VERSION 5.8 ;
BUSBITCHARS "[]" ;
DIVIDERCHAR "/" ;
UNITS
    DATABASE MICRONS 1000 ;
END UNITS

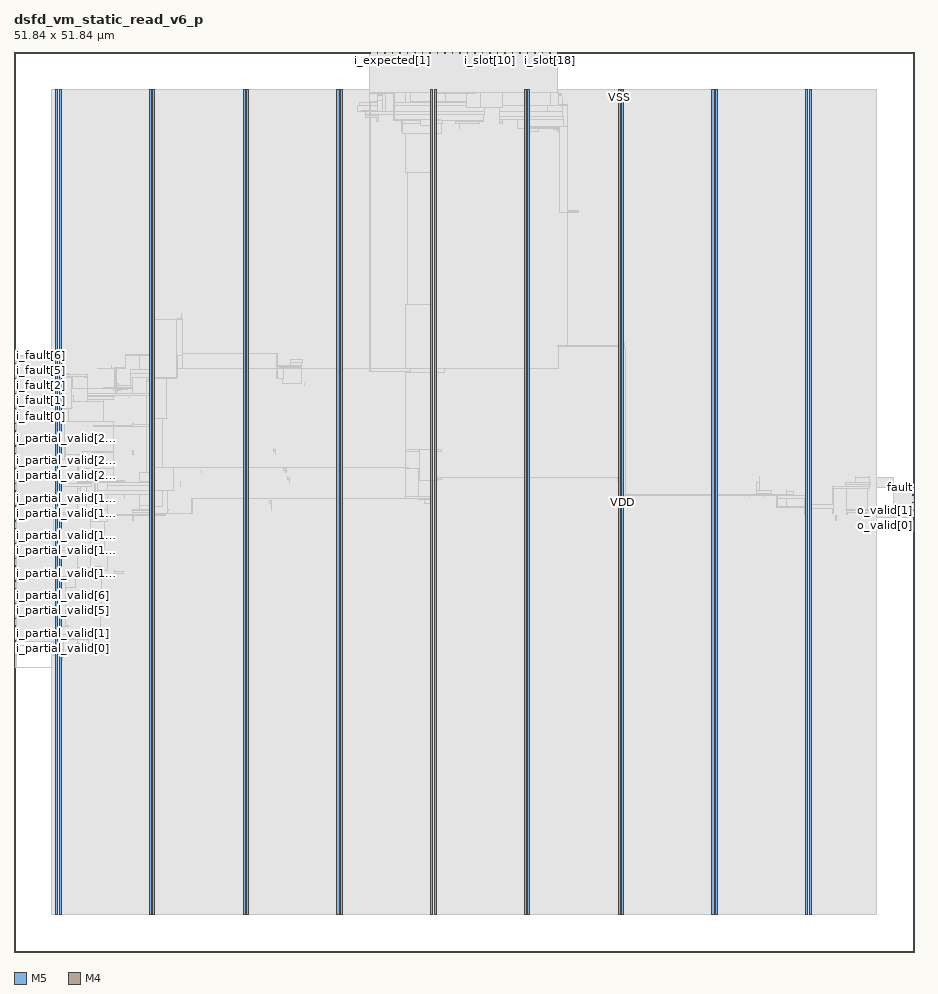
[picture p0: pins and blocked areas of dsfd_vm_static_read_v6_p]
MACRO dsfd_vm_static_read_v6_p
  FOREIGN dsfd_vm_static_read_v6_p 0 0 ;
  CLASS BLOCK ;
  SIZE 51.84 BY 51.84 ;
  PIN ck
    DIRECTION INPUT ;
    USE SIGNAL ;
    PORT
      LAYER M5 ;
        RECT  20.496 51.756 20.52 51.84 ;
    END
  END ck
  PIN fault
    DIRECTION OUTPUT ;
    USE SIGNAL ;
    PORT
      LAYER M4 ;
        RECT  51.756 26.736 51.84 26.76 ;
    END
  END fault
  PIN i_expected[0]
    DIRECTION INPUT ;
    USE SIGNAL ;
    PORT
      LAYER M5 ;
        RECT  21.36 51.756 21.384 51.84 ;
    END
  END i_expected[0]
  PIN i_expected[1]
    DIRECTION INPUT ;
    USE SIGNAL ;
    PORT
      LAYER M5 ;
        RECT  21.792 51.756 21.816 51.84 ;
    END
  END i_expected[1]
  PIN i_expected[2]
    DIRECTION INPUT ;
    USE SIGNAL ;
    PORT
      LAYER M5 ;
        RECT  22.224 51.756 22.248 51.84 ;
    END
  END i_expected[2]
  PIN i_expected[3]
    DIRECTION INPUT ;
    USE SIGNAL ;
    PORT
      LAYER M5 ;
        RECT  22.656 51.756 22.68 51.84 ;
    END
  END i_expected[3]
  PIN i_fault[0]
    DIRECTION INPUT ;
    USE SIGNAL ;
    PORT
      LAYER M4 ;
        RECT  0 31.296 0.084 31.32 ;
    END
  END i_fault[0]
  PIN i_fault[1]
    DIRECTION INPUT ;
    USE SIGNAL ;
    PORT
      LAYER M4 ;
        RECT  0 31.728 0.084 31.752 ;
    END
  END i_fault[1]
  PIN i_fault[2]
    DIRECTION INPUT ;
    USE SIGNAL ;
    PORT
      LAYER M4 ;
        RECT  0 32.16 0.084 32.184 ;
    END
  END i_fault[2]
  PIN i_fault[3]
    DIRECTION INPUT ;
    USE SIGNAL ;
    PORT
      LAYER M4 ;
        RECT  0 32.592 0.084 32.616 ;
    END
  END i_fault[3]
  PIN i_fault[4]
    DIRECTION INPUT ;
    USE SIGNAL ;
    PORT
      LAYER M4 ;
        RECT  0 33.024 0.084 33.048 ;
    END
  END i_fault[4]
  PIN i_fault[5]
    DIRECTION INPUT ;
    USE SIGNAL ;
    PORT
      LAYER M4 ;
        RECT  0 33.456 0.084 33.48 ;
    END
  END i_fault[5]
  PIN i_fault[6]
    DIRECTION INPUT ;
    USE SIGNAL ;
    PORT
      LAYER M4 ;
        RECT  0 33.888 0.084 33.912 ;
    END
  END i_fault[6]
  PIN i_fault[7]
    DIRECTION INPUT ;
    USE SIGNAL ;
    PORT
      LAYER M4 ;
        RECT  0 34.32 0.084 34.344 ;
    END
  END i_fault[7]
  PIN i_partial_valid[0]
    DIRECTION INPUT ;
    USE SIGNAL ;
    PORT
      LAYER M4 ;
        RECT  0 17.472 0.084 17.496 ;
    END
  END i_partial_valid[0]
  PIN i_partial_valid[10]
    DIRECTION INPUT ;
    USE SIGNAL ;
    PORT
      LAYER M4 ;
        RECT  0 21.792 0.084 21.816 ;
    END
  END i_partial_valid[10]
  PIN i_partial_valid[11]
    DIRECTION INPUT ;
    USE SIGNAL ;
    PORT
      LAYER M4 ;
        RECT  0 22.224 0.084 22.248 ;
    END
  END i_partial_valid[11]
  PIN i_partial_valid[12]
    DIRECTION INPUT ;
    USE SIGNAL ;
    PORT
      LAYER M4 ;
        RECT  0 22.656 0.084 22.68 ;
    END
  END i_partial_valid[12]
  PIN i_partial_valid[13]
    DIRECTION INPUT ;
    USE SIGNAL ;
    PORT
      LAYER M4 ;
        RECT  0 23.088 0.084 23.112 ;
    END
  END i_partial_valid[13]
  PIN i_partial_valid[14]
    DIRECTION INPUT ;
    USE SIGNAL ;
    PORT
      LAYER M4 ;
        RECT  0 23.52 0.084 23.544 ;
    END
  END i_partial_valid[14]
  PIN i_partial_valid[15]
    DIRECTION INPUT ;
    USE SIGNAL ;
    PORT
      LAYER M4 ;
        RECT  0 23.952 0.084 23.976 ;
    END
  END i_partial_valid[15]
  PIN i_partial_valid[16]
    DIRECTION INPUT ;
    USE SIGNAL ;
    PORT
      LAYER M4 ;
        RECT  0 24.384 0.084 24.408 ;
    END
  END i_partial_valid[16]
  PIN i_partial_valid[17]
    DIRECTION INPUT ;
    USE SIGNAL ;
    PORT
      LAYER M4 ;
        RECT  0 24.816 0.084 24.84 ;
    END
  END i_partial_valid[17]
  PIN i_partial_valid[18]
    DIRECTION INPUT ;
    USE SIGNAL ;
    PORT
      LAYER M4 ;
        RECT  0 25.248 0.084 25.272 ;
    END
  END i_partial_valid[18]
  PIN i_partial_valid[19]
    DIRECTION INPUT ;
    USE SIGNAL ;
    PORT
      LAYER M4 ;
        RECT  0 25.68 0.084 25.704 ;
    END
  END i_partial_valid[19]
  PIN i_partial_valid[1]
    DIRECTION INPUT ;
    USE SIGNAL ;
    PORT
      LAYER M4 ;
        RECT  0 17.904 0.084 17.928 ;
    END
  END i_partial_valid[1]
  PIN i_partial_valid[20]
    DIRECTION INPUT ;
    USE SIGNAL ;
    PORT
      LAYER M4 ;
        RECT  0 26.112 0.084 26.136 ;
    END
  END i_partial_valid[20]
  PIN i_partial_valid[21]
    DIRECTION INPUT ;
    USE SIGNAL ;
    PORT
      LAYER M4 ;
        RECT  0 26.544 0.084 26.568 ;
    END
  END i_partial_valid[21]
  PIN i_partial_valid[22]
    DIRECTION INPUT ;
    USE SIGNAL ;
    PORT
      LAYER M4 ;
        RECT  0 26.976 0.084 27 ;
    END
  END i_partial_valid[22]
  PIN i_partial_valid[23]
    DIRECTION INPUT ;
    USE SIGNAL ;
    PORT
      LAYER M4 ;
        RECT  0 27.408 0.084 27.432 ;
    END
  END i_partial_valid[23]
  PIN i_partial_valid[24]
    DIRECTION INPUT ;
    USE SIGNAL ;
    PORT
      LAYER M4 ;
        RECT  0 27.84 0.084 27.864 ;
    END
  END i_partial_valid[24]
  PIN i_partial_valid[25]
    DIRECTION INPUT ;
    USE SIGNAL ;
    PORT
      LAYER M4 ;
        RECT  0 28.272 0.084 28.296 ;
    END
  END i_partial_valid[25]
  PIN i_partial_valid[26]
    DIRECTION INPUT ;
    USE SIGNAL ;
    PORT
      LAYER M4 ;
        RECT  0 28.704 0.084 28.728 ;
    END
  END i_partial_valid[26]
  PIN i_partial_valid[27]
    DIRECTION INPUT ;
    USE SIGNAL ;
    PORT
      LAYER M4 ;
        RECT  0 29.136 0.084 29.16 ;
    END
  END i_partial_valid[27]
  PIN i_partial_valid[28]
    DIRECTION INPUT ;
    USE SIGNAL ;
    PORT
      LAYER M4 ;
        RECT  0 29.568 0.084 29.592 ;
    END
  END i_partial_valid[28]
  PIN i_partial_valid[29]
    DIRECTION INPUT ;
    USE SIGNAL ;
    PORT
      LAYER M4 ;
        RECT  0 30 0.084 30.024 ;
    END
  END i_partial_valid[29]
  PIN i_partial_valid[2]
    DIRECTION INPUT ;
    USE SIGNAL ;
    PORT
      LAYER M4 ;
        RECT  0 18.336 0.084 18.36 ;
    END
  END i_partial_valid[2]
  PIN i_partial_valid[30]
    DIRECTION INPUT ;
    USE SIGNAL ;
    PORT
      LAYER M4 ;
        RECT  0 30.432 0.084 30.456 ;
    END
  END i_partial_valid[30]
  PIN i_partial_valid[31]
    DIRECTION INPUT ;
    USE SIGNAL ;
    PORT
      LAYER M4 ;
        RECT  0 30.864 0.084 30.888 ;
    END
  END i_partial_valid[31]
  PIN i_partial_valid[3]
    DIRECTION INPUT ;
    USE SIGNAL ;
    PORT
      LAYER M4 ;
        RECT  0 18.768 0.084 18.792 ;
    END
  END i_partial_valid[3]
  PIN i_partial_valid[4]
    DIRECTION INPUT ;
    USE SIGNAL ;
    PORT
      LAYER M4 ;
        RECT  0 19.2 0.084 19.224 ;
    END
  END i_partial_valid[4]
  PIN i_partial_valid[5]
    DIRECTION INPUT ;
    USE SIGNAL ;
    PORT
      LAYER M4 ;
        RECT  0 19.632 0.084 19.656 ;
    END
  END i_partial_valid[5]
  PIN i_partial_valid[6]
    DIRECTION INPUT ;
    USE SIGNAL ;
    PORT
      LAYER M4 ;
        RECT  0 20.064 0.084 20.088 ;
    END
  END i_partial_valid[6]
  PIN i_partial_valid[7]
    DIRECTION INPUT ;
    USE SIGNAL ;
    PORT
      LAYER M4 ;
        RECT  0 20.496 0.084 20.52 ;
    END
  END i_partial_valid[7]
  PIN i_partial_valid[8]
    DIRECTION INPUT ;
    USE SIGNAL ;
    PORT
      LAYER M4 ;
        RECT  0 20.928 0.084 20.952 ;
    END
  END i_partial_valid[8]
  PIN i_partial_valid[9]
    DIRECTION INPUT ;
    USE SIGNAL ;
    PORT
      LAYER M4 ;
        RECT  0 21.36 0.084 21.384 ;
    END
  END i_partial_valid[9]
  PIN i_slot[0]
    DIRECTION INPUT ;
    USE SIGNAL ;
    PORT
      LAYER M5 ;
        RECT  23.088 51.756 23.112 51.84 ;
    END
  END i_slot[0]
  PIN i_slot[10]
    DIRECTION INPUT ;
    USE SIGNAL ;
    PORT
      LAYER M5 ;
        RECT  27.408 51.756 27.432 51.84 ;
    END
  END i_slot[10]
  PIN i_slot[11]
    DIRECTION INPUT ;
    USE SIGNAL ;
    PORT
      LAYER M5 ;
        RECT  27.84 51.756 27.864 51.84 ;
    END
  END i_slot[11]
  PIN i_slot[12]
    DIRECTION INPUT ;
    USE SIGNAL ;
    PORT
      LAYER M5 ;
        RECT  28.272 51.756 28.296 51.84 ;
    END
  END i_slot[12]
  PIN i_slot[13]
    DIRECTION INPUT ;
    USE SIGNAL ;
    PORT
      LAYER M5 ;
        RECT  28.704 51.756 28.728 51.84 ;
    END
  END i_slot[13]
  PIN i_slot[14]
    DIRECTION INPUT ;
    USE SIGNAL ;
    PORT
      LAYER M5 ;
        RECT  29.136 51.756 29.16 51.84 ;
    END
  END i_slot[14]
  PIN i_slot[15]
    DIRECTION INPUT ;
    USE SIGNAL ;
    PORT
      LAYER M5 ;
        RECT  29.568 51.756 29.592 51.84 ;
    END
  END i_slot[15]
  PIN i_slot[16]
    DIRECTION INPUT ;
    USE SIGNAL ;
    PORT
      LAYER M5 ;
        RECT  30 51.756 30.024 51.84 ;
    END
  END i_slot[16]
  PIN i_slot[17]
    DIRECTION INPUT ;
    USE SIGNAL ;
    PORT
      LAYER M5 ;
        RECT  30.432 51.756 30.456 51.84 ;
    END
  END i_slot[17]
  PIN i_slot[18]
    DIRECTION INPUT ;
    USE SIGNAL ;
    PORT
      LAYER M5 ;
        RECT  30.864 51.756 30.888 51.84 ;
    END
  END i_slot[18]
  PIN i_slot[19]
    DIRECTION INPUT ;
    USE SIGNAL ;
    PORT
      LAYER M5 ;
        RECT  31.296 51.756 31.32 51.84 ;
    END
  END i_slot[19]
  PIN i_slot[1]
    DIRECTION INPUT ;
    USE SIGNAL ;
    PORT
      LAYER M5 ;
        RECT  23.52 51.756 23.544 51.84 ;
    END
  END i_slot[1]
  PIN i_slot[2]
    DIRECTION INPUT ;
    USE SIGNAL ;
    PORT
      LAYER M5 ;
        RECT  23.952 51.756 23.976 51.84 ;
    END
  END i_slot[2]
  PIN i_slot[3]
    DIRECTION INPUT ;
    USE SIGNAL ;
    PORT
      LAYER M5 ;
        RECT  24.384 51.756 24.408 51.84 ;
    END
  END i_slot[3]
  PIN i_slot[4]
    DIRECTION INPUT ;
    USE SIGNAL ;
    PORT
      LAYER M5 ;
        RECT  24.816 51.756 24.84 51.84 ;
    END
  END i_slot[4]
  PIN i_slot[5]
    DIRECTION INPUT ;
    USE SIGNAL ;
    PORT
      LAYER M5 ;
        RECT  25.248 51.756 25.272 51.84 ;
    END
  END i_slot[5]
  PIN i_slot[6]
    DIRECTION INPUT ;
    USE SIGNAL ;
    PORT
      LAYER M5 ;
        RECT  25.68 51.756 25.704 51.84 ;
    END
  END i_slot[6]
  PIN i_slot[7]
    DIRECTION INPUT ;
    USE SIGNAL ;
    PORT
      LAYER M5 ;
        RECT  26.112 51.756 26.136 51.84 ;
    END
  END i_slot[7]
  PIN i_slot[8]
    DIRECTION INPUT ;
    USE SIGNAL ;
    PORT
      LAYER M5 ;
        RECT  26.544 51.756 26.568 51.84 ;
    END
  END i_slot[8]
  PIN i_slot[9]
    DIRECTION INPUT ;
    USE SIGNAL ;
    PORT
      LAYER M5 ;
        RECT  26.976 51.756 27 51.84 ;
    END
  END i_slot[9]
  PIN o_valid[0]
    DIRECTION OUTPUT ;
    USE SIGNAL ;
    PORT
      LAYER M4 ;
        RECT  51.756 25.008 51.84 25.032 ;
    END
  END o_valid[0]
  PIN o_valid[1]
    DIRECTION OUTPUT ;
    USE SIGNAL ;
    PORT
      LAYER M4 ;
        RECT  51.756 25.44 51.84 25.464 ;
    END
  END o_valid[1]
  PIN o_valid[2]
    DIRECTION OUTPUT ;
    USE SIGNAL ;
    PORT
      LAYER M4 ;
        RECT  51.756 25.872 51.84 25.896 ;
    END
  END o_valid[2]
  PIN o_valid[3]
    DIRECTION OUTPUT ;
    USE SIGNAL ;
    PORT
      LAYER M4 ;
        RECT  51.756 26.304 51.84 26.328 ;
    END
  END o_valid[3]
  PIN rst_n
    DIRECTION INPUT ;
    USE SIGNAL ;
    PORT
      LAYER M5 ;
        RECT  20.928 51.756 20.952 51.84 ;
    END
  END rst_n
  PIN VDD
    DIRECTION INOUT ;
    USE POWER ;
    PORT
      LAYER M5 ;
        RECT  45.792 2.151 45.912 49.689 ;
        RECT  40.392 2.151 40.512 49.689 ;
        RECT  34.992 2.151 35.112 49.689 ;
        RECT  29.592 2.151 29.712 49.689 ;
        RECT  24.192 2.151 24.312 49.689 ;
        RECT  18.792 2.151 18.912 49.689 ;
        RECT  13.392 2.151 13.512 49.689 ;
        RECT  7.992 2.151 8.112 49.689 ;
        RECT  2.592 2.151 2.712 49.689 ;
    END
  END VDD
  PIN VSS
    DIRECTION INOUT ;
    USE GROUND ;
    PORT
      LAYER M5 ;
        RECT  45.6 2.137 45.72 49.703 ;
        RECT  40.2 2.137 40.32 49.703 ;
        RECT  34.8 2.137 34.92 49.703 ;
        RECT  29.4 2.137 29.52 49.703 ;
        RECT  24 2.137 24.12 49.703 ;
        RECT  18.6 2.137 18.72 49.703 ;
        RECT  13.2 2.137 13.32 49.703 ;
        RECT  7.8 2.137 7.92 49.703 ;
        RECT  2.4 2.137 2.52 49.703 ;
    END
  END VSS
  # OT_OBS_CLOSED layer=M5 d_um=1.536 added=2
  OBS
    LAYER RVTN ;
     RECT  2.16 2.16 49.68 2.295 ;
     RECT  2.16 2.565 49.68 2.835 ;
     RECT  2.16 3.105 49.68 3.375 ;
     RECT  2.16 3.645 49.68 3.915 ;
     RECT  2.16 4.185 49.68 4.455 ;
     RECT  2.16 4.725 49.68 4.995 ;
     RECT  2.16 5.265 49.68 5.535 ;
     RECT  2.16 5.805 49.68 6.075 ;
     RECT  2.16 6.345 49.68 6.615 ;
     RECT  2.16 6.885 49.68 7.155 ;
     RECT  2.16 7.425 49.68 7.695 ;
     RECT  2.16 7.965 49.68 8.235 ;
     RECT  2.16 8.505 49.68 8.775 ;
     RECT  2.16 9.045 49.68 9.315 ;
     RECT  2.16 9.585 49.68 9.855 ;
     RECT  2.16 10.125 49.68 10.395 ;
     RECT  2.16 10.665 49.68 10.935 ;
     RECT  2.16 11.205 49.68 11.475 ;
     RECT  2.16 11.745 49.68 12.015 ;
     RECT  2.16 12.285 49.68 12.555 ;
     RECT  2.16 12.825 49.68 13.095 ;
     RECT  2.16 13.365 49.68 13.635 ;
     RECT  2.16 13.905 49.68 14.175 ;
     RECT  2.16 14.445 49.68 14.715 ;
     RECT  2.16 14.985 49.68 15.255 ;
     RECT  2.16 15.525 49.68 15.795 ;
     RECT  2.16 16.065 49.68 16.335 ;
     RECT  2.16 16.605 49.68 16.875 ;
     RECT  2.16 17.145 49.68 17.415 ;
     RECT  2.16 17.685 49.68 17.955 ;
     RECT  2.16 18.225 49.68 18.495 ;
     RECT  2.16 18.765 49.68 19.035 ;
     RECT  2.16 19.305 49.68 19.575 ;
     RECT  2.16 19.845 49.68 20.115 ;
     RECT  2.16 20.385 49.68 20.655 ;
     RECT  2.16 20.925 49.68 21.195 ;
     RECT  2.16 21.465 49.68 21.735 ;
     RECT  2.16 22.005 49.68 22.275 ;
     RECT  2.16 22.545 49.68 22.815 ;
     RECT  2.16 23.085 49.68 23.355 ;
     RECT  2.16 23.625 49.68 23.895 ;
     RECT  2.16 24.165 49.68 24.435 ;
     RECT  2.16 24.705 49.68 24.975 ;
     RECT  2.16 25.245 49.68 25.515 ;
     RECT  2.16 25.785 49.68 26.055 ;
     RECT  2.16 26.325 49.68 26.595 ;
     RECT  2.16 26.865 49.68 27.135 ;
     RECT  2.16 27.405 49.68 27.675 ;
     RECT  2.16 27.945 49.68 28.215 ;
     RECT  2.16 28.485 49.68 28.755 ;
     RECT  2.16 29.025 49.68 29.295 ;
     RECT  2.16 29.565 49.68 29.835 ;
     RECT  2.16 30.105 49.68 30.375 ;
     RECT  2.16 30.645 49.68 30.915 ;
     RECT  2.16 31.185 49.68 31.455 ;
     RECT  2.16 31.725 49.68 31.995 ;
     RECT  2.16 32.265 49.68 32.535 ;
     RECT  2.16 32.805 49.68 33.075 ;
     RECT  2.16 33.345 49.68 33.615 ;
     RECT  2.16 33.885 49.68 34.155 ;
     RECT  2.16 34.425 49.68 34.695 ;
     RECT  2.16 34.965 49.68 35.235 ;
     RECT  2.16 35.505 49.68 35.775 ;
     RECT  2.16 36.045 49.68 36.315 ;
     RECT  2.16 36.585 49.68 36.855 ;
     RECT  2.16 37.125 49.68 37.395 ;
     RECT  2.16 37.665 49.68 37.935 ;
     RECT  2.16 38.205 49.68 38.475 ;
     RECT  2.16 38.745 49.68 39.015 ;
     RECT  2.16 39.285 49.68 39.555 ;
     RECT  2.16 39.825 49.68 40.095 ;
     RECT  2.16 40.365 49.68 40.635 ;
     RECT  2.16 40.905 49.68 41.175 ;
     RECT  2.16 41.445 49.68 41.715 ;
     RECT  2.16 41.985 49.68 42.255 ;
     RECT  2.16 42.525 49.68 42.795 ;
     RECT  2.16 43.065 49.68 43.335 ;
     RECT  2.16 43.605 49.68 43.875 ;
     RECT  2.16 44.145 49.68 44.415 ;
     RECT  2.16 44.685 49.68 44.955 ;
     RECT  2.16 45.225 49.68 45.495 ;
     RECT  2.16 45.765 49.68 46.035 ;
     RECT  2.16 46.305 49.68 46.575 ;
     RECT  2.16 46.845 49.68 47.115 ;
     RECT  2.16 47.385 49.68 47.655 ;
     RECT  2.16 47.925 49.68 48.195 ;
     RECT  2.16 48.465 49.68 48.735 ;
     RECT  2.16 49.005 49.68 49.275 ;
     RECT  2.16 49.545 49.68 49.68 ;
    LAYER RVTP ;
     RECT  2.16 2.295 49.68 2.565 ;
     RECT  2.16 2.835 49.68 3.105 ;
     RECT  2.16 3.375 49.68 3.645 ;
     RECT  2.16 3.915 49.68 4.185 ;
     RECT  2.16 4.455 49.68 4.725 ;
     RECT  2.16 4.995 49.68 5.265 ;
     RECT  2.16 5.535 49.68 5.805 ;
     RECT  2.16 6.075 49.68 6.345 ;
     RECT  2.16 6.615 49.68 6.885 ;
     RECT  2.16 7.155 49.68 7.425 ;
     RECT  2.16 7.695 49.68 7.965 ;
     RECT  2.16 8.235 49.68 8.505 ;
     RECT  2.16 8.775 49.68 9.045 ;
     RECT  2.16 9.315 49.68 9.585 ;
     RECT  2.16 9.855 49.68 10.125 ;
     RECT  2.16 10.395 49.68 10.665 ;
     RECT  2.16 10.935 49.68 11.205 ;
     RECT  2.16 11.475 49.68 11.745 ;
     RECT  2.16 12.015 49.68 12.285 ;
     RECT  2.16 12.555 49.68 12.825 ;
     RECT  2.16 13.095 49.68 13.365 ;
     RECT  2.16 13.635 49.68 13.905 ;
     RECT  2.16 14.175 49.68 14.445 ;
     RECT  2.16 14.715 49.68 14.985 ;
     RECT  2.16 15.255 49.68 15.525 ;
     RECT  2.16 15.795 49.68 16.065 ;
     RECT  2.16 16.335 49.68 16.605 ;
     RECT  2.16 16.875 49.68 17.145 ;
     RECT  2.16 17.415 49.68 17.685 ;
     RECT  2.16 17.955 49.68 18.225 ;
     RECT  2.16 18.495 49.68 18.765 ;
     RECT  2.16 19.035 49.68 19.305 ;
     RECT  2.16 19.575 49.68 19.845 ;
     RECT  2.16 20.115 49.68 20.385 ;
     RECT  2.16 20.655 49.68 20.925 ;
     RECT  2.16 21.195 49.68 21.465 ;
     RECT  2.16 21.735 49.68 22.005 ;
     RECT  2.16 22.275 49.68 22.545 ;
     RECT  2.16 22.815 49.68 23.085 ;
     RECT  2.16 23.355 49.68 23.625 ;
     RECT  2.16 23.895 49.68 24.165 ;
     RECT  2.16 24.435 49.68 24.705 ;
     RECT  2.16 24.975 49.68 25.245 ;
     RECT  2.16 25.515 49.68 25.785 ;
     RECT  2.16 26.055 49.68 26.325 ;
     RECT  2.16 26.595 49.68 26.865 ;
     RECT  2.16 27.135 49.68 27.405 ;
     RECT  2.16 27.675 49.68 27.945 ;
     RECT  2.16 28.215 49.68 28.485 ;
     RECT  2.16 28.755 49.68 29.025 ;
     RECT  2.16 29.295 49.68 29.565 ;
     RECT  2.16 29.835 49.68 30.105 ;
     RECT  2.16 30.375 49.68 30.645 ;
     RECT  2.16 30.915 49.68 31.185 ;
     RECT  2.16 31.455 49.68 31.725 ;
     RECT  2.16 31.995 49.68 32.265 ;
     RECT  2.16 32.535 49.68 32.805 ;
     RECT  2.16 33.075 49.68 33.345 ;
     RECT  2.16 33.615 49.68 33.885 ;
     RECT  2.16 34.155 49.68 34.425 ;
     RECT  2.16 34.695 49.68 34.965 ;
     RECT  2.16 35.235 49.68 35.505 ;
     RECT  2.16 35.775 49.68 36.045 ;
     RECT  2.16 36.315 49.68 36.585 ;
     RECT  2.16 36.855 49.68 37.125 ;
     RECT  2.16 37.395 49.68 37.665 ;
     RECT  2.16 37.935 49.68 38.205 ;
     RECT  2.16 38.475 49.68 38.745 ;
     RECT  2.16 39.015 49.68 39.285 ;
     RECT  2.16 39.555 49.68 39.825 ;
     RECT  2.16 40.095 49.68 40.365 ;
     RECT  2.16 40.635 49.68 40.905 ;
     RECT  2.16 41.175 49.68 41.445 ;
     RECT  2.16 41.715 49.68 41.985 ;
     RECT  2.16 42.255 49.68 42.525 ;
     RECT  2.16 42.795 49.68 43.065 ;
     RECT  2.16 43.335 49.68 43.605 ;
     RECT  2.16 43.875 49.68 44.145 ;
     RECT  2.16 44.415 49.68 44.685 ;
     RECT  2.16 44.955 49.68 45.225 ;
     RECT  2.16 45.495 49.68 45.765 ;
     RECT  2.16 46.035 49.68 46.305 ;
     RECT  2.16 46.575 49.68 46.845 ;
     RECT  2.16 47.115 49.68 47.385 ;
     RECT  2.16 47.655 49.68 47.925 ;
     RECT  2.16 48.195 49.68 48.465 ;
     RECT  2.16 48.735 49.68 49.005 ;
     RECT  2.16 49.275 49.68 49.545 ;
    LAYER M1 ;
     RECT  2.16 2.151 49.68 49.689 ;
    LAYER M2 ;
     RECT  0.103 16.38 2.16 16.398 ;
     RECT  0.103 17.658 2.16 17.676 ;
     RECT  0.103 22.05 2.16 22.068 ;
     RECT  0.103 26.91 2.16 26.928 ;
     RECT  0.103 28.962 2.16 28.98 ;
     RECT  2.16 2.151 49.68 49.689 ;
     RECT  49.68 26.766 50.675 27.324 ;
     RECT  49.68 25.02 50.711 25.47 ;
     RECT  50.675 26.766 50.711 26.784 ;
     RECT  50.711 25.326 50.747 25.344 ;
    LAYER M3 ;
     RECT  2.415 2.143 2.505 2.413 ;
     RECT  7.815 2.143 7.905 2.413 ;
     RECT  13.215 2.143 13.305 2.413 ;
     RECT  18.615 2.143 18.705 2.413 ;
     RECT  24.015 2.143 24.105 2.413 ;
     RECT  29.415 2.143 29.505 2.413 ;
     RECT  34.815 2.143 34.905 2.413 ;
     RECT  40.215 2.143 40.305 2.413 ;
     RECT  45.615 2.143 45.705 2.413 ;
     RECT  2.415 2.413 2.697 16.411 ;
     RECT  2.412 16.411 2.697 16.501 ;
     RECT  2.412 16.501 2.754 16.807 ;
     RECT  2.412 16.807 2.79 16.951 ;
     RECT  2.412 16.951 2.826 17.077 ;
     RECT  2.304 17.077 2.826 17.419 ;
     RECT  3.672 17.581 3.69 17.725 ;
     RECT  3.672 17.725 4.302 17.761 ;
     RECT  2.304 17.419 2.862 17.995 ;
     RECT  3.636 17.761 4.302 17.995 ;
     RECT  2.304 17.995 4.302 18.031 ;
     RECT  2.304 18.031 4.77 18.301 ;
     RECT  0.108 16.375 0.126 18.797 ;
     RECT  2.304 18.301 4.986 19.651 ;
     RECT  5.796 21.667 5.814 21.811 ;
     RECT  5.796 21.811 6.282 21.929 ;
     RECT  5.796 21.929 5.814 21.965 ;
     RECT  2.304 19.651 5.058 21.973 ;
     RECT  0.108 21.355 0.126 22.253 ;
     RECT  2.304 21.973 5.382 22.891 ;
     RECT  2.304 22.891 5.706 23.009 ;
     RECT  2.304 23.009 5.382 23.081 ;
     RECT  2.304 23.081 5.202 23.431 ;
     RECT  2.268 23.431 5.202 24.781 ;
     RECT  7.815 2.413 8.097 25.141 ;
     RECT  47.34 24.871 47.358 25.169 ;
     RECT  6.84 24.871 6.858 25.177 ;
     RECT  7.815 25.141 8.73 25.177 ;
     RECT  45.615 2.413 45.897 25.213 ;
     RECT  48.96 25.015 48.978 25.285 ;
     RECT  6.84 25.177 8.73 25.321 ;
     RECT  47.952 25.177 48.006 25.321 ;
     RECT  48.96 25.285 49.158 25.321 ;
     RECT  50.688 25.003 50.706 25.321 ;
     RECT  6.84 25.321 8.802 25.411 ;
     RECT  47.952 25.321 49.158 25.411 ;
     RECT  2.268 24.781 5.382 25.475 ;
     RECT  50.688 25.321 50.742 25.475 ;
     RECT  6.84 25.411 8.874 25.511 ;
     RECT  47.952 25.411 49.338 25.511 ;
     RECT  45.504 25.213 45.897 25.519 ;
     RECT  47.16 25.249 47.178 25.519 ;
     RECT  43.92 25.627 43.938 25.681 ;
     RECT  7.2 25.511 8.802 25.709 ;
     RECT  45.504 25.519 47.178 25.781 ;
     RECT  14.832 25.411 14.85 25.825 ;
     RECT  24.015 2.413 24.297 25.825 ;
     RECT  50.724 25.475 50.742 25.901 ;
     RECT  14.724 25.825 14.85 25.979 ;
     RECT  14.724 25.979 14.742 26.015 ;
     RECT  23.652 25.825 24.297 26.059 ;
     RECT  23.292 26.059 24.297 26.095 ;
     RECT  43.92 25.681 44.514 26.095 ;
     RECT  45.504 25.781 45.897 26.095 ;
     RECT  22.392 26.095 22.41 26.131 ;
     RECT  23.184 26.095 24.297 26.131 ;
     RECT  22.392 26.131 24.297 26.141 ;
     RECT  22.536 26.141 24.297 26.249 ;
     RECT  43.92 26.095 45.897 26.285 ;
     RECT  42.372 26.257 42.39 26.293 ;
     RECT  43.164 26.257 43.182 26.293 ;
     RECT  6.336 26.095 6.354 26.329 ;
     RECT  7.2 25.709 8.334 26.329 ;
     RECT  42.372 26.293 43.182 26.333 ;
     RECT  43.92 26.285 44.874 26.333 ;
     RECT  2.304 25.475 5.382 26.365 ;
     RECT  6.336 26.329 8.334 26.365 ;
     RECT  42.768 26.333 43.182 26.401 ;
     RECT  44.496 26.333 44.874 26.519 ;
     RECT  42.768 26.401 43.65 26.555 ;
     RECT  2.304 26.365 8.334 26.599 ;
     RECT  44.496 26.519 44.514 26.627 ;
     RECT  47.16 25.781 47.178 26.671 ;
     RECT  47.952 25.511 49.158 26.671 ;
     RECT  2.304 26.599 8.514 26.699 ;
     RECT  50.652 26.299 50.67 26.731 ;
     RECT  2.304 26.699 8.442 26.789 ;
     RECT  47.16 26.671 49.266 26.789 ;
     RECT  50.652 26.731 50.706 26.789 ;
     RECT  47.88 26.789 49.266 26.905 ;
     RECT  2.304 26.789 8.118 27.059 ;
     RECT  42.768 26.555 42.93 27.059 ;
     RECT  47.88 26.905 49.338 27.059 ;
     RECT  2.304 27.059 6.354 27.095 ;
     RECT  7.2 27.059 8.118 27.095 ;
     RECT  9.576 26.797 9.594 27.095 ;
     RECT  2.376 27.095 6.354 27.131 ;
     RECT  23.292 26.249 24.297 27.163 ;
     RECT  34.815 2.413 35.097 27.163 ;
     RECT  15.876 27.031 15.894 27.211 ;
     RECT  23.292 27.163 24.39 27.211 ;
     RECT  15.732 27.211 15.894 27.329 ;
     RECT  23.292 27.211 24.606 27.329 ;
     RECT  48.456 27.059 49.266 27.329 ;
     RECT  50.652 26.789 50.67 27.329 ;
     RECT  23.292 27.329 24.39 27.341 ;
     RECT  34.776 27.163 35.097 27.341 ;
     RECT  15.732 27.329 15.75 27.365 ;
     RECT  48.456 27.329 48.474 27.365 ;
     RECT  49.248 27.329 49.266 27.365 ;
     RECT  42.912 27.059 42.93 27.401 ;
     RECT  0.108 26.905 0.126 27.437 ;
     RECT  7.2 27.095 8.097 27.599 ;
     RECT  10.8 27.607 10.818 27.707 ;
     RECT  15.66 27.607 15.678 27.751 ;
     RECT  2.376 27.131 5.706 27.835 ;
     RECT  15.516 27.751 15.678 27.869 ;
     RECT  22.536 26.249 22.554 27.877 ;
     RECT  23.292 27.341 24.297 27.877 ;
     RECT  15.516 27.869 15.534 27.905 ;
     RECT  15.048 28.651 15.066 28.831 ;
     RECT  22.536 27.877 24.297 28.831 ;
     RECT  6.84 28.651 6.858 28.859 ;
     RECT  14.94 28.831 15.066 28.949 ;
     RECT  22.536 28.831 24.606 28.949 ;
     RECT  14.94 28.949 14.958 28.985 ;
     RECT  0.108 28.957 0.126 29.165 ;
     RECT  6.84 30.283 6.858 30.413 ;
     RECT  2.304 27.835 5.706 30.569 ;
     RECT  2.304 30.569 5.166 31.721 ;
     RECT  4.212 31.721 5.166 31.801 ;
     RECT  4.212 31.801 5.706 31.999 ;
     RECT  4.212 31.999 5.778 32.035 ;
     RECT  6.66 31.927 6.678 32.035 ;
     RECT  7.632 27.599 8.097 32.035 ;
     RECT  2.304 31.721 3.402 32.063 ;
     RECT  4.212 32.035 6.678 32.071 ;
     RECT  7.632 32.035 8.442 32.071 ;
     RECT  2.304 32.063 2.97 32.099 ;
     RECT  2.304 32.099 2.934 32.189 ;
     RECT  4.212 32.071 8.442 32.189 ;
     RECT  2.304 32.189 2.862 32.225 ;
     RECT  4.212 32.189 6.822 32.477 ;
     RECT  5.148 32.477 6.822 32.495 ;
     RECT  5.76 32.495 6.822 32.639 ;
     RECT  5.76 32.639 5.994 32.729 ;
     RECT  16.74 32.611 16.758 32.729 ;
     RECT  15.48 32.737 15.498 32.773 ;
     RECT  16.272 32.737 16.578 32.773 ;
     RECT  7.632 32.189 8.442 32.881 ;
     RECT  7.632 32.881 8.766 32.999 ;
     RECT  2.304 32.225 2.697 33.067 ;
     RECT  4.212 32.477 4.23 33.115 ;
     RECT  6.732 32.639 6.822 33.115 ;
     RECT  7.632 32.999 8.55 33.115 ;
     RECT  2.304 33.067 3.294 33.151 ;
     RECT  4.068 33.115 4.23 33.151 ;
     RECT  2.304 33.151 4.23 33.269 ;
     RECT  2.304 33.269 3.15 33.305 ;
     RECT  6.732 33.115 8.55 33.341 ;
     RECT  22.536 28.949 24.297 33.355 ;
     RECT  6.732 33.341 8.442 33.539 ;
     RECT  22.536 33.355 24.786 33.539 ;
     RECT  2.304 33.305 2.79 33.575 ;
     RECT  5.76 32.729 5.814 33.595 ;
     RECT  4.824 33.583 4.842 33.629 ;
     RECT  25.884 33.583 25.902 33.629 ;
     RECT  5.76 33.595 6.426 33.647 ;
     RECT  15.48 32.773 16.578 33.691 ;
     RECT  15.264 33.691 16.578 33.739 ;
     RECT  5.616 33.655 5.634 33.809 ;
     RECT  15.12 33.739 16.578 33.809 ;
     RECT  2.415 33.575 2.79 33.917 ;
     RECT  15.912 33.809 16.578 33.961 ;
     RECT  15.912 33.961 16.614 34.115 ;
     RECT  16.596 34.115 16.614 34.151 ;
     RECT  2.415 33.917 2.697 34.315 ;
     RECT  7.2 33.539 8.442 34.349 ;
     RECT  7.2 34.349 8.097 34.357 ;
     RECT  2.34 34.315 2.697 34.385 ;
     RECT  6.408 33.647 6.426 34.397 ;
     RECT  7.164 34.357 8.097 34.397 ;
     RECT  34.815 27.341 35.097 34.795 ;
     RECT  34.815 34.795 35.19 35.069 ;
     RECT  9.396 36.379 9.414 36.475 ;
     RECT  9.396 36.475 9.666 36.509 ;
     RECT  9.648 36.509 9.666 36.779 ;
     RECT  22.536 33.539 24.297 37.319 ;
     RECT  32.508 42.601 32.526 42.715 ;
     RECT  31.86 42.715 32.526 42.719 ;
     RECT  31.86 42.719 31.878 42.755 ;
     RECT  22.644 37.319 24.297 44.887 ;
     RECT  22.572 44.887 24.297 47.119 ;
     RECT  22.572 47.119 24.606 47.155 ;
     RECT  29.415 2.413 29.697 47.281 ;
     RECT  31.392 47.191 31.41 47.281 ;
     RECT  31.32 47.281 31.41 47.353 ;
     RECT  29.415 47.281 30.186 47.461 ;
     RECT  31.068 47.353 31.662 47.461 ;
     RECT  25.668 47.425 25.686 47.695 ;
     RECT  22.356 47.155 24.606 47.731 ;
     RECT  25.668 47.695 26.118 47.731 ;
     RECT  25.452 47.731 26.838 47.821 ;
     RECT  27.972 47.731 28.134 47.821 ;
     RECT  20.952 47.821 20.97 47.857 ;
     RECT  25.452 47.821 26.91 47.857 ;
     RECT  22.356 47.731 24.678 47.893 ;
     RECT  25.452 47.857 27.018 47.893 ;
     RECT  22.356 47.893 27.018 47.899 ;
     RECT  27.936 47.821 28.134 47.965 ;
     RECT  28.98 47.461 31.662 47.965 ;
     RECT  20.88 47.857 20.97 48.091 ;
     RECT  27.936 47.965 31.662 48.119 ;
     RECT  20.232 48.091 20.97 48.199 ;
     RECT  20.232 48.199 21.006 48.235 ;
     RECT  21.888 47.899 27.018 48.235 ;
     RECT  27.936 48.119 31.59 48.389 ;
     RECT  20.232 48.235 27.09 48.424 ;
     RECT  20.052 48.424 27.09 48.433 ;
     RECT  19.764 48.433 27.09 48.731 ;
     RECT  19.872 48.731 27.09 48.763 ;
     RECT  27.936 48.389 30.726 48.763 ;
     RECT  19.872 48.763 30.726 48.929 ;
     RECT  31.572 48.389 31.59 49.199 ;
     RECT  20.7 48.929 30.726 49.315 ;
     RECT  20.7 49.315 31.554 49.379 ;
     RECT  2.415 34.385 2.697 49.427 ;
     RECT  7.815 34.397 8.097 49.427 ;
     RECT  13.215 2.413 13.497 49.427 ;
     RECT  18.615 2.413 18.897 49.427 ;
     RECT  34.815 35.069 35.097 49.427 ;
     RECT  40.215 2.413 40.497 49.427 ;
     RECT  45.615 26.285 45.897 49.427 ;
     RECT  20.772 49.379 31.554 49.469 ;
     RECT  20.952 49.469 31.338 49.517 ;
     RECT  26.856 49.517 30.834 49.565 ;
     RECT  20.952 49.517 21.258 49.577 ;
     RECT  22.104 49.517 25.038 49.577 ;
     RECT  26.856 49.565 30.438 49.577 ;
     RECT  2.415 49.427 2.505 49.697 ;
     RECT  7.815 49.427 7.905 49.697 ;
     RECT  13.215 49.427 13.305 49.697 ;
     RECT  18.615 49.427 18.705 49.697 ;
     RECT  23.832 49.577 24.105 49.697 ;
     RECT  29.415 49.577 29.574 49.697 ;
     RECT  34.815 49.427 34.905 49.697 ;
     RECT  40.215 49.427 40.305 49.697 ;
     RECT  45.615 49.427 45.705 49.697 ;
     RECT  29.556 49.697 29.574 49.805 ;
     RECT  22.104 49.577 22.122 50.765 ;
     RECT  23.832 49.697 23.85 50.765 ;
     RECT  25.02 49.577 25.038 50.765 ;
     RECT  27.288 49.577 27.306 50.765 ;
    LAYER M4 ;
     RECT  0.06 17.472 0.137 34.344 ;
     RECT  0.137 17.904 2.408 34.344 ;
     RECT  2.408 2.148 2.512 49.692 ;
     RECT  2.512 2.418 2.704 49.422 ;
     RECT  2.704 32.448 2.801 33.912 ;
     RECT  2.704 19.872 2.909 26.712 ;
     RECT  2.909 19.872 2.915 23.928 ;
     RECT  2.909 24.912 2.945 26.712 ;
     RECT  2.704 27.696 2.981 29.112 ;
     RECT  2.704 18.768 3.125 18.792 ;
     RECT  2.704 30.576 3.125 31.368 ;
     RECT  3.125 31.344 3.347 31.368 ;
     RECT  2.801 32.448 3.347 33.096 ;
     RECT  2.945 24.912 3.449 25.032 ;
     RECT  2.915 20.976 3.557 23.928 ;
     RECT  3.557 21.648 3.683 23.928 ;
     RECT  2.981 27.696 3.737 28.632 ;
     RECT  2.915 19.872 3.773 19.896 ;
     RECT  2.945 26.112 3.805 26.712 ;
     RECT  3.737 28.08 3.809 28.632 ;
     RECT  3.449 25.008 3.881 25.032 ;
     RECT  3.809 28.224 3.949 28.632 ;
     RECT  3.805 26.112 4.165 27.048 ;
     RECT  3.683 22.176 4.403 23.928 ;
     RECT  3.949 28.224 4.493 28.824 ;
     RECT  4.403 23.328 4.637 23.352 ;
     RECT  4.165 25.152 4.637 27.048 ;
     RECT  4.637 26.352 4.709 27.048 ;
     RECT  4.709 26.496 4.817 27.048 ;
     RECT  4.403 22.176 5.033 22.2 ;
     RECT  4.817 26.592 5.393 27.048 ;
     RECT  3.347 32.448 5.713 32.472 ;
     RECT  4.493 28.8 5.717 28.824 ;
     RECT  5.713 32.352 5.845 32.472 ;
     RECT  5.845 32.208 5.932 32.472 ;
     RECT  5.932 32.352 5.933 32.472 ;
     RECT  5.933 32.352 6.113 32.424 ;
     RECT  4.813 33.6 6.397 33.624 ;
     RECT  6.397 33.6 6.437 34.392 ;
     RECT  6.113 32.4 6.545 32.424 ;
     RECT  4.561 30.288 6.829 30.312 ;
     RECT  4.637 25.152 7.808 25.176 ;
     RECT  5.393 26.592 7.808 26.856 ;
     RECT  6.829 30.288 7.808 30.408 ;
     RECT  6.437 34.368 7.808 34.392 ;
     RECT  7.808 2.148 7.912 49.692 ;
     RECT  7.912 2.418 8.104 49.422 ;
     RECT  8.104 30.384 8.579 30.744 ;
     RECT  8.104 25.248 8.813 26.616 ;
     RECT  8.579 30.72 8.819 30.744 ;
     RECT  8.813 26.592 9.203 26.616 ;
     RECT  8.104 33.072 9.349 33.096 ;
     RECT  8.104 34.368 9.349 34.392 ;
     RECT  9.349 33.072 9.395 34.392 ;
     RECT  9.341 36.384 9.425 36.408 ;
     RECT  9.395 33.6 9.685 34.392 ;
     RECT  9.637 36.48 9.731 36.504 ;
     RECT  8.813 25.248 10.213 25.272 ;
     RECT  10.213 25.248 10.259 26.136 ;
     RECT  10.259 26.112 13.208 26.136 ;
     RECT  9.157 27.888 13.208 27.912 ;
     RECT  9.685 33.6 13.208 34.488 ;
     RECT  13.208 2.148 13.312 49.692 ;
     RECT  13.312 2.418 13.504 49.422 ;
     RECT  13.504 33.6 15.109 34.488 ;
     RECT  15.109 33.024 15.155 34.488 ;
     RECT  15.155 33.024 15.509 33.624 ;
     RECT  13.504 26.112 18.608 26.136 ;
     RECT  13.504 27.888 18.608 27.912 ;
     RECT  15.509 33.6 18.608 33.624 ;
     RECT  18.608 2.148 18.712 49.692 ;
     RECT  18.712 2.418 18.904 49.422 ;
     RECT  18.904 33.6 20.485 33.624 ;
     RECT  20.041 48.432 20.917 48.456 ;
     RECT  20.917 48.432 21.229 49.032 ;
     RECT  21.229 48.432 21.395 49.56 ;
     RECT  21.395 48.432 21.877 49.512 ;
     RECT  21.877 47.904 21.917 49.512 ;
     RECT  22.093 50.736 22.259 50.76 ;
     RECT  21.917 47.904 22.316 47.928 ;
     RECT  22.316 47.28 22.403 47.928 ;
     RECT  18.904 26.112 22.421 26.136 ;
     RECT  21.917 48.912 22.525 49.512 ;
     RECT  18.904 27.888 22.745 27.912 ;
     RECT  20.485 33.456 22.813 33.624 ;
     RECT  22.525 48.912 22.853 49.56 ;
     RECT  22.403 47.904 23.389 47.928 ;
     RECT  23.821 50.736 23.987 50.76 ;
     RECT  23.279 27.168 24.008 27.192 ;
     RECT  23.276 28.896 24.008 28.92 ;
     RECT  22.813 33.36 24.008 33.624 ;
     RECT  23.389 47.616 24.008 47.928 ;
     RECT  22.853 49.008 24.008 49.56 ;
     RECT  24.008 2.148 24.112 49.692 ;
     RECT  24.112 2.418 24.304 49.56 ;
     RECT  24.304 27.168 24.401 27.336 ;
     RECT  24.304 47.904 24.545 47.928 ;
     RECT  24.304 33.36 24.797 33.624 ;
     RECT  24.304 49.008 24.851 49.56 ;
     RECT  25.009 50.736 25.283 50.76 ;
     RECT  24.851 49.008 26.089 49.512 ;
     RECT  26.089 48.672 26.845 49.512 ;
     RECT  27.277 50.736 27.443 50.76 ;
     RECT  26.845 48.672 28.109 49.56 ;
     RECT  24.401 27.312 29.408 27.336 ;
     RECT  24.797 33.6 29.408 33.624 ;
     RECT  28.109 48.768 29.408 49.56 ;
     RECT  29.408 2.148 29.512 49.692 ;
     RECT  29.512 2.418 29.516 49.692 ;
     RECT  29.516 2.418 29.603 49.8 ;
     RECT  29.603 2.418 29.704 49.56 ;
     RECT  29.704 48.768 30.899 49.56 ;
     RECT  30.899 48.768 31.372 49.512 ;
     RECT  29.704 33.6 31.379 33.624 ;
     RECT  29.704 47.52 31.521 47.544 ;
     RECT  31.429 42.624 31.82 42.648 ;
     RECT  31.82 42.624 31.907 42.744 ;
     RECT  31.372 48.768 31.907 48.792 ;
     RECT  31.907 42.624 32.537 42.648 ;
     RECT  29.704 27.312 34.765 27.336 ;
     RECT  34.765 27.168 34.808 27.336 ;
     RECT  31.333 34.896 34.808 34.92 ;
     RECT  34.808 2.148 34.912 49.692 ;
     RECT  34.912 2.418 35.104 49.422 ;
     RECT  35.104 26.304 35.219 27.192 ;
     RECT  35.104 34.8 35.245 34.824 ;
     RECT  35.219 26.304 40.208 26.328 ;
     RECT  40.208 2.148 40.312 49.692 ;
     RECT  40.312 2.418 40.504 49.422 ;
     RECT  40.504 26.304 43.909 26.328 ;
     RECT  43.909 25.632 43.949 26.328 ;
     RECT  43.949 25.632 45.529 25.656 ;
     RECT  45.529 25.536 45.608 25.656 ;
     RECT  45.608 2.148 45.712 49.692 ;
     RECT  45.712 2.418 45.904 49.422 ;
     RECT  45.904 25.536 47.189 25.56 ;
     RECT  50.641 26.304 50.677 26.328 ;
     RECT  50.677 25.008 51.804 26.76 ;
    LAYER M5 ;
     RECT  2.4 2.137 2.52 2.151 ;
     RECT  7.8 2.137 7.92 2.151 ;
     RECT  13.2 2.137 13.32 2.151 ;
     RECT  18.6 2.137 18.72 2.151 ;
     RECT  24 2.137 24.12 2.151 ;
     RECT  29.4 2.137 29.52 2.151 ;
     RECT  34.8 2.137 34.92 2.151 ;
     RECT  40.2 2.137 40.32 2.151 ;
     RECT  45.6 2.137 45.72 2.151 ;
     RECT  2.4 2.151 2.712 18.757 ;
     RECT  2.4 18.757 2.952 21.637 ;
     RECT  2.4 21.637 3.672 23.125 ;
     RECT  2.4 23.125 4.392 23.317 ;
     RECT  2.304 23.317 4.392 25.187 ;
     RECT  2.304 25.187 3.672 25.331 ;
     RECT  7.8 2.151 8.112 25.669 ;
     RECT  10.224 25.237 10.248 26.147 ;
     RECT  34.8 2.151 35.112 26.293 ;
     RECT  7.8 25.669 8.568 26.581 ;
     RECT  2.4 25.331 3.672 26.821 ;
     RECT  2.4 26.821 4.44 26.963 ;
     RECT  24 2.151 24.312 27.157 ;
     RECT  7.8 26.581 9.192 27.923 ;
     RECT  2.4 26.963 3.672 28.355 ;
     RECT  23.328 27.157 24.312 28.931 ;
     RECT  7.8 27.923 8.568 30.709 ;
     RECT  2.4 28.355 2.904 31.333 ;
     RECT  7.8 30.709 8.808 33.061 ;
     RECT  2.4 31.333 3.336 33.107 ;
     RECT  7.8 33.061 9.384 33.107 ;
     RECT  5.856 32.197 5.88 33.635 ;
     RECT  9.36 33.107 9.384 34.357 ;
     RECT  15.12 33.013 15.144 34.499 ;
     RECT  34.8 26.293 35.208 34.835 ;
     RECT  31.344 33.589 31.368 34.885 ;
     RECT  31.344 34.885 31.896 34.931 ;
     RECT  9.36 34.357 9.72 36.419 ;
     RECT  9.696 36.419 9.72 36.515 ;
     RECT  31.872 34.931 31.896 42.613 ;
     RECT  31.44 42.613 31.896 47.555 ;
     RECT  22.368 47.269 22.392 47.939 ;
     RECT  31.872 47.555 31.896 48.803 ;
     RECT  20.496 33.445 20.52 48.997 ;
     RECT  20.496 48.997 20.952 49.477 ;
     RECT  20.496 49.477 21.816 49.525 ;
     RECT  24 28.931 24.312 49.525 ;
     RECT  25.68 49.477 26.568 49.525 ;
     RECT  29.4 2.151 29.712 49.525 ;
     RECT  31.296 49.477 31.32 49.525 ;
     RECT  2.4 33.107 2.712 49.689 ;
     RECT  7.8 33.107 8.112 49.689 ;
     RECT  13.2 2.151 13.512 49.689 ;
     RECT  18.6 2.151 18.912 49.689 ;
     RECT  34.8 34.835 35.112 49.689 ;
     RECT  40.2 2.151 40.512 49.689 ;
     RECT  45.6 2.151 45.912 49.689 ;
     RECT  2.4 49.689 2.52 49.703 ;
     RECT  7.8 49.689 7.92 49.703 ;
     RECT  13.2 49.689 13.32 49.703 ;
     RECT  18.6 49.689 18.72 49.703 ;
     RECT  34.8 49.689 34.92 49.703 ;
     RECT  40.2 49.689 40.32 49.703 ;
     RECT  45.6 49.689 45.72 49.703 ;
     RECT  20.496 49.525 31.32 51.792 ;
     RECT  8.112 33.107 9.36 36.419 ;
     RECT  24.312 49.477 25.68 49.525 ;
  END
END dsfd_vm_static_read_v6_p
END LIBRARY
